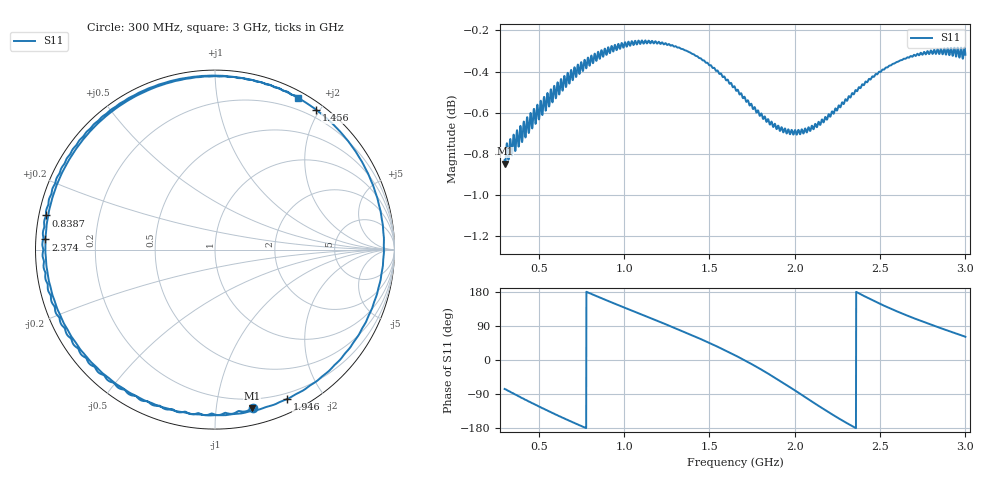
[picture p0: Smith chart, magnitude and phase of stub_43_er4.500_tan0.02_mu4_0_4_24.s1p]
! Chirptenna · simulación 3D de un stub abierto
# HZ S RI R 50
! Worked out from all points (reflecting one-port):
!   2001 points, 300 MHz to 3 GHz, reference 50 ohm
!   lowest |S11| = -0.8 dB at 302.7 MHz (marker M1), VSWR 20.49, Z = 6.29 - j62.6 ohm
!   phase of S11 starts at -76 deg and turns -582 deg over the sweep
!   S11 on the Smith chart (normalised r, x): 300 MHz: 0.12, -1.26; 838.6 MHz: 0.02, +0.10; 1.456 GHz: 0.10, +1.96; 1.946 GHz: 0.14, -1.58; 2.374 GHz: 0.03, +0.03; 3 GHz: 0.07, +1.69
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3e8  0.2137 -0.8833
3.027e8  0.2064 -0.8831
3.8235e8  -0.092 -0.911
4.6065e8  -0.3734 -0.8466
5.4435e8  -0.6256 -0.6971
6.375e8  -0.8343 -0.4453
7.3875e8  -0.9447 -0.1301
8.3865e8  -0.9418 0.1901
9.75e8  -0.774 0.5801
1.1532e9  -0.3449 0.9068
1.3125e9  0.1412 0.9575
1.4556e9  0.5649 0.7779
1.55955e9  0.8038 0.5132
1.65e9  0.9242 0.2041
1.7202e9  0.9368 -0.0668
1.7958e9  0.8567 -0.366
1.87005e9  0.6772 -0.6326
1.94565e9  0.401 -0.833
1.9875e9  0.2167 -0.8971
2.055e9  -0.0978 -0.9181
2.1306e9  -0.4386 -0.8152
2.2305e9  -0.7785 -0.5145
2.325e9  -0.9309 -0.1388
2.3736e9  -0.9446 0.0567
2.5248e9  -0.7635 0.5755
2.6625e9  -0.4309 0.8608
2.82585e9  0.0199 0.9643
3e9  0.4646 0.8446
